VERSION 5.8 ;
BUSBITCHARS "[]" ;
DIVIDERCHAR "/" ;
CLEARANCEMEASURE EUCLIDEAN ;

SITE coresite_DH_P
    SIZE 0.0450 BY 0.2880 ;
    CLASS CORE ;
    SYMMETRY X Y ;
END coresite_DH_P

SITE coresite_DH_N
    SIZE 0.0450 BY 0.2880 ;
    CLASS CORE ;
    SYMMETRY X Y ;
END coresite_DH_N

SITE coresite
    SIZE 0.0450 BY 0.1440 ;
    CLASS CORE ;
    SYMMETRY X Y ;
END coresite

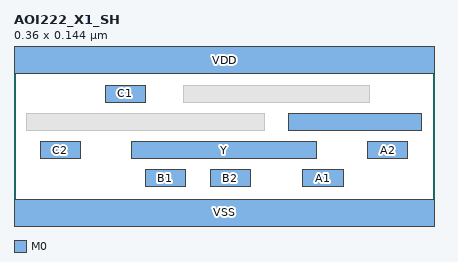
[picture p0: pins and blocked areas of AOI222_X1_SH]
MACRO AOI222_X1_SH
  CLASS CORE ;
  ORIGIN 0 0 ;
  FOREIGN AOI222_X1_SH 0 0 ;
  SIZE 0.3600 BY 0.1440 ;
  SYMMETRY X Y ;
  SITE coresite ;
  PIN B1
    DIRECTION INPUT ;
    USE SIGNAL ;
    PORT
      LAYER M0 ;
        RECT 0.1125 0.0430 0.1470 0.0290 ;
    END
  END B1
  PIN B2
    DIRECTION INPUT ;
    USE SIGNAL ;
    PORT
      LAYER M0 ;
        RECT 0.1680 0.0430 0.2025 0.0290 ;
    END
  END B2
  PIN A1
    DIRECTION INPUT ;
    USE SIGNAL ;
    PORT
      LAYER M0 ;
        RECT 0.2475 0.0430 0.2820 0.0290 ;
    END
  END A1
  PIN C2
    DIRECTION INPUT ;
    USE SIGNAL ;
    PORT
      LAYER M0 ;
        RECT 0.0225 0.0670 0.0570 0.0530 ;
    END
  END C2
  PIN Y
    DIRECTION OUTPUT ;
    USE SIGNAL ;
    PORT
      LAYER M0 ;
        RECT 0.1005 0.0670 0.2595 0.0530 ;
        RECT 0.2355 0.0910 0.3495 0.0770 ;
    END
  END Y
  PIN A2
    DIRECTION INPUT ;
    USE SIGNAL ;
    PORT
      LAYER M0 ;
        RECT 0.3030 0.0670 0.3375 0.0530 ;
    END
  END A2
  PIN C1
    DIRECTION INPUT ;
    USE SIGNAL ;
    PORT
      LAYER M0 ;
        RECT 0.0780 0.1150 0.1125 0.1010 ;
    END
  END C1
  PIN VSS
    DIRECTION INOUT ;
    USE GROUND ;
    SHAPE ABUTMENT ;
    PORT
      LAYER M0 ;
        RECT 0.0000 -0.0180 0.3600 0.0180 ;
    END
  END VSS
  PIN VDD
    DIRECTION INOUT ;
    USE POWER ;
    SHAPE ABUTMENT ;
    PORT
      LAYER M0 ;
        RECT 0.0000 0.1260 0.3600 0.1620 ;
    END
  END VDD
  OBS
      LAYER M0 ;
        RECT 0.0105 0.0770 0.2145 0.0910 ;
        RECT 0.1455 0.1010 0.3045 0.1150 ;
  END
END AOI222_X1_SH

END LIBRARY
